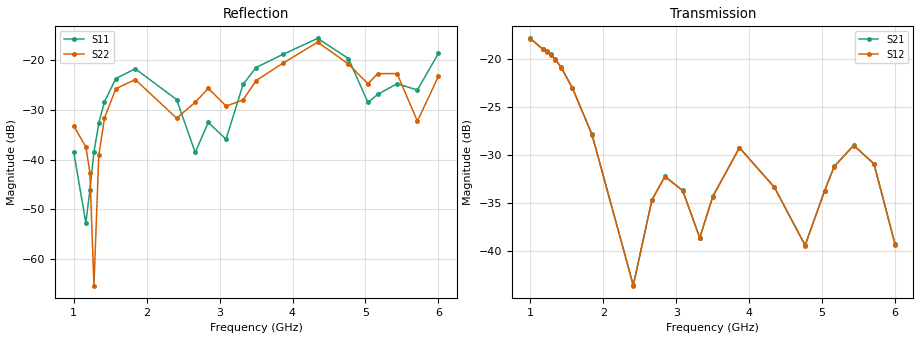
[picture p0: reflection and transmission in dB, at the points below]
!Agilent Technologies,E8364B,MY43040528,A.07.50.67
!Agilent E8364B: A.07.50.67
!Date: Sunday, March 01, 2026 17:02:12
!Correction: S11(Full 2 Port(1,2))
!S21(Full 2 Port(1,2))
!S12(Full 2 Port(1,2))
!S22(Full 2 Port(1,2))
!S2P File: Measurements: S11, S21, S12, S22:
# Hz S  dB  R 50
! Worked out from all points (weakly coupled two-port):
!   451 points, 1 GHz to 6 GHz, reference 50 ohm
!   highest |S21| = -17.84 dB at 1 GHz (marker M1); lowest = -43.6 dB at 2.411 GHz (marker M2)
!   lowest |S11| = -52.7 dB at 1.167 GHz (marker M3), VSWR 1.00, Z = 49.9 + j0.216 ohm
!   |S11| at or under -10 dB: start of sweep to end of sweep
!   |S22| runs from -65.3 to -16.3 dB; largest |S21 - S12| = 0.00059
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1e9  -38.44 24.4  -17.84 28.2  -17.88 28.2  -33.22 -2.3
1.166667e9  -52.70 111.2  -18.92 -21.6  -18.95 -21.5  -37.44 -7.3
1.222222e9  -46.17 174.6  -19.19 -39.1  -19.23 -39.1  -42.61 -15.3
1.277778e9  -38.48 -171.0  -19.52 -57.3  -19.56 -57.2  -65.34 -46.1
1.344444e9  -32.64 -175.9  -20.04 -79.7  -20.08 -79.6  -39.16 123.4
1.422222e9  -28.38 168.4  -20.86 -106.0  -20.89 -106.0  -31.64 105.5
1.577778e9  -23.72 134.5  -23.02 -157.5  -23.06 -157.5  -25.77 61.0
1.844444e9  -21.76 82.1  -27.85 118.7  -27.88 118.8  -23.93 -5.0
2.411111e9  -27.95 -4.9  -43.59 -129.1  -43.64 -129.1  -31.69 -82.0
2.666667e9  -38.58 39.4  -34.68 66.9  -34.72 66.9  -28.49 -57.9
2.844444e9  -32.54 47.0  -32.23 -7.6  -32.27 -7.5  -25.69 -91.3
3.088889e9  -35.91 71.6  -33.70 -98.3  -33.74 -98.3  -29.25 -131.2
3.322222e9  -24.89 80.3  -38.64 -138.1  -38.68 -138.0  -28.03 -108.2
3.5e9  -21.51 52.4  -34.33 -158.0  -34.37 -157.9  -24.13 -130.0
3.866667e9  -18.88 15.4  -29.23 73.3  -29.27 73.4  -20.66 -166.1
4.344444e9  -15.65 -51.2  -33.35 -103.3  -33.39 -103.3  -16.41 111.6
4.766667e9  -19.70 -115.3  -39.42 56.4  -39.45 56.4  -20.81 39.2
5.033333e9  -28.53 -114.7  -33.74 -98.4  -33.77 -98.3  -24.78 40.6
5.166667e9  -26.91 -85.2  -31.17 -160.7  -31.21 -160.7  -22.74 34.1
5.433333e9  -24.76 -106.2  -28.99 82.7  -29.02 82.6  -22.72 -16.9
5.711111e9  -26.02 -71.6  -30.92 -34.6  -30.96 -34.6  -32.28 -16.3
6e9  -18.68 -92.0  -39.32 -137.9  -39.36 -137.9  -23.29 -16.2
